VERSION 5.7 ;
  NOWIREEXTENSIONATPIN ON ;
  DIVIDERCHAR "/" ;
  BUSBITCHARS "[]" ;
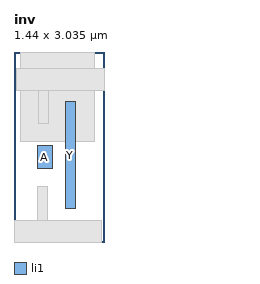
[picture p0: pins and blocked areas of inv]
MACRO inv
  CLASS BLOCK ;
  FOREIGN inv ;
  ORIGIN 0.610 0.795 ;
  SIZE 1.440 BY 3.035 ;
  PIN Y
    ANTENNADIFFAREA 0.247800 ;
    PORT
      LAYER li1 ;
        RECT 0.205 -0.265 0.375 1.450 ;
    END
  END Y
  PIN A
    ANTENNAGATEAREA 0.126000 ;
    PORT
      LAYER li1 ;
        RECT -0.240 0.375 0.000 0.750 ;
    END
  END A
  OBS
      LAYER nwell ;
        RECT -0.500 0.805 0.680 2.240 ;
      LAYER li1 ;
        RECT -0.565 1.625 0.830 1.970 ;
        RECT -0.225 1.105 -0.055 1.625 ;
        RECT -0.240 -0.450 -0.070 0.095 ;
        RECT -0.610 -0.795 0.785 -0.450 ;
  END
END inv
END LIBRARY

